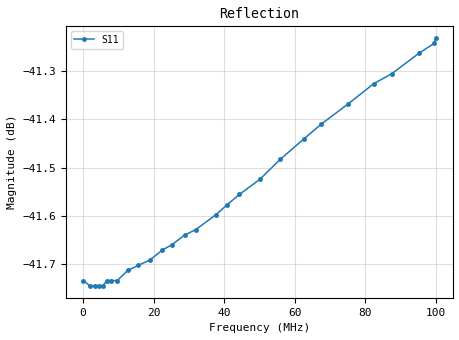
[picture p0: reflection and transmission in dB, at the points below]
! ListType=Lin
!!SAA-2 female load 0.1 to 100MHz 500 points
# MHz S RI R 50
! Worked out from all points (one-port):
!   500 points, 100 kHz to 100 MHz, reference 50 ohm
!   lowest |S11| = -41.7 dB at 3.503 MHz (marker M1), VSWR 1.02, Z = 50.8 - j0.000559 ohm
!   |S11| at or under -10 dB: start of sweep to end of sweep
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0.1  0.00819 -2.18e-05
1.901804  0.00818 -1.24e-05
3.503407  0.00818 -5.5e-06
4.504409  0.00818 -1.8e-06
5.705611  0.00818 1.8e-06
6.706613  0.00819 4.3e-06
7.907816  0.00819 6.6e-06
9.709619  0.00819 8.5e-06
12.71263  0.00821 9.4e-06
15.71563  0.00822 9e-06
18.91884  0.00823 7.1e-06
22.52244  0.00825 3.2e-06
25.12505  0.00826 -8e-07
28.92886  0.00828 -8.4e-06
31.93186  0.00829 -1.59e-05
37.73768  0.00832 -3.4e-05
40.94088  0.00834 -4.61e-05
44.34429  0.00836 -6.06e-05
50.1501  0.00839 -8.91e-05
55.95591  0.00843 -0.00012
62.56253  0.00847 -0.000156
67.56754  0.0085 -0.000183
75.17515  0.00854 -0.000225
82.38236  0.00858 -0.000266
87.58758  0.0086 -0.000295
95.19519  0.00864 -0.000339
99.5996  0.00866 -0.000364
100  0.00867 -0.000367
